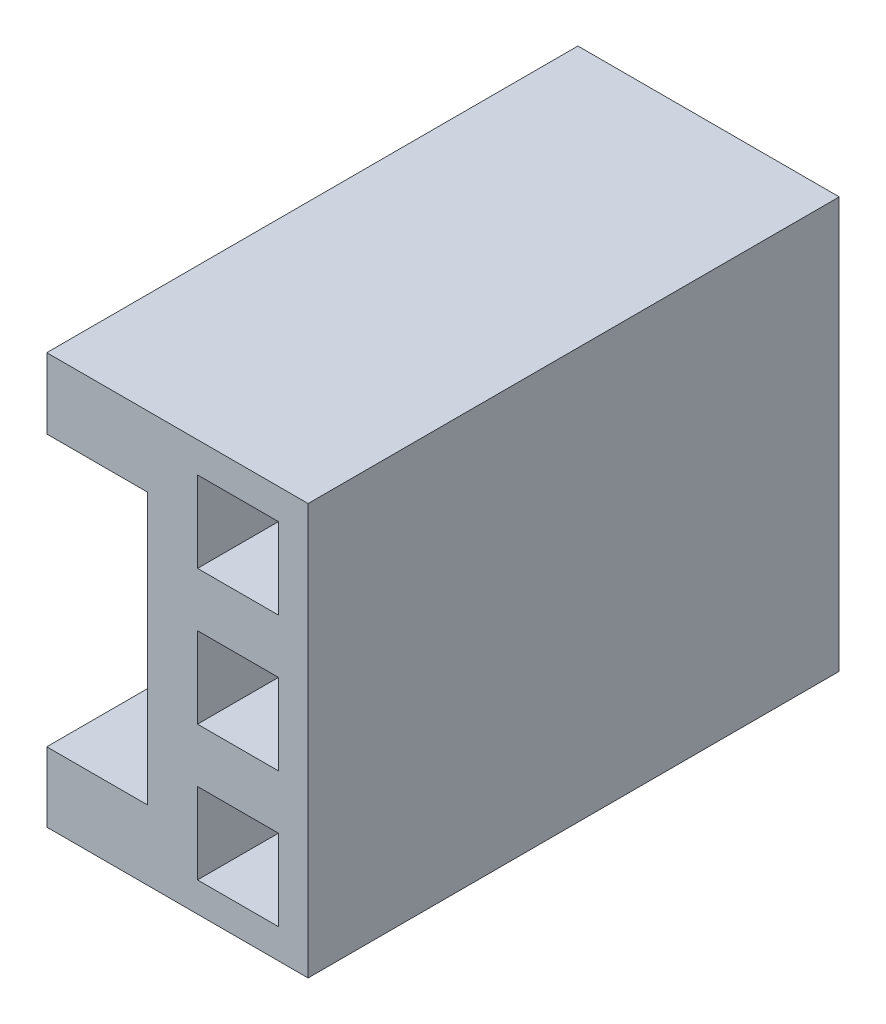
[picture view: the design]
ISO-10303-21;
HEADER;
FILE_DESCRIPTION(('STEP AP214'),'2;1');
FILE_NAME('part.step','',(''),(''),'','','');
FILE_SCHEMA(('AUTOMOTIVE_DESIGN { 1 0 10303 214 1 1 1 1 }'));
ENDSEC;
DATA;
#1=APPLICATION_CONTEXT('core data for automotive mechanical design processes');
#2=APPLICATION_PROTOCOL_DEFINITION('international standard','automotive_design',2000,#1);
#3=PRODUCT_CONTEXT('',#1,'mechanical');
#4=PRODUCT('Part','Part','',(#3));
#5=PRODUCT_RELATED_PRODUCT_CATEGORY('part','',(#4));
#6=PRODUCT_DEFINITION_FORMATION('','',#4);
#7=PRODUCT_DEFINITION_CONTEXT('part definition',#1,'design');
#8=PRODUCT_DEFINITION('design','',#6,#7);
#9=PRODUCT_DEFINITION_SHAPE('','',#8);
#10=(LENGTH_UNIT() NAMED_UNIT(*) SI_UNIT(.MILLI.,.METRE.));
#11=(NAMED_UNIT(*) PLANE_ANGLE_UNIT() SI_UNIT($,.RADIAN.));
#12=(NAMED_UNIT(*) SI_UNIT($,.STERADIAN.) SOLID_ANGLE_UNIT());
#13=UNCERTAINTY_MEASURE_WITH_UNIT(LENGTH_MEASURE(1.E-05),#10,'distance_accuracy_value','');
#14=(GEOMETRIC_REPRESENTATION_CONTEXT(3) GLOBAL_UNCERTAINTY_ASSIGNED_CONTEXT((#13)) GLOBAL_UNIT_ASSIGNED_CONTEXT((#10,
#11,#12)) REPRESENTATION_CONTEXT('',''));
#15=CARTESIAN_POINT('',(0.,0.,0.));
#16=DIRECTION('',(0.,0.,1.));
#17=DIRECTION('',(1.,0.,0.));
#18=AXIS2_PLACEMENT_3D('',#15,#16,#17);
#19=CARTESIAN_POINT('',(-1.69999999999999,-2.54999999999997,10.));
#20=DIRECTION('',(-1.,0.,0.));
#21=DIRECTION('',(0.,0.,1.));
#22=AXIS2_PLACEMENT_3D('',#19,#20,#21);
#23=PLANE('',#22);
#24=DIRECTION('',(0.,0.,-1.));
#25=VECTOR('',#24,1.);
#26=CARTESIAN_POINT('',(-1.69999999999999,-2.54999999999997,10.));
#27=LINE('',#26,#25);
#28=CARTESIAN_POINT('',(-1.69999999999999,-2.54999999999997,1.99999999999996));
#29=VERTEX_POINT('',#28);
#30=CARTESIAN_POINT('',(-1.69999999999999,-2.54999999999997,0.));
#31=VERTEX_POINT('',#30);
#32=EDGE_CURVE('E493',#29,#31,#27,.T.);
#33=ORIENTED_EDGE('',*,*,#32,.F.);
#34=DIRECTION('',(0.,1.,0.));
#35=VECTOR('',#34,1.);
#36=CARTESIAN_POINT('',(-1.69999999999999,-4.56556443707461,1.99999999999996));
#37=LINE('',#36,#35);
#38=CARTESIAN_POINT('',(-1.69999999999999,2.55000000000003,1.99999999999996));
#39=VERTEX_POINT('',#38);
#40=EDGE_CURVE('E291',#29,#39,#37,.T.);
#41=ORIENTED_EDGE('',*,*,#40,.T.);
#42=DIRECTION('',(0.,0.,-1.));
#43=VECTOR('',#42,1.);
#44=CARTESIAN_POINT('',(-1.69999999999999,2.55000000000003,10.));
#45=LINE('',#44,#43);
#46=CARTESIAN_POINT('',(-1.69999999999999,2.55000000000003,0.));
#47=VERTEX_POINT('',#46);
#48=EDGE_CURVE('E490',#39,#47,#45,.T.);
#49=ORIENTED_EDGE('',*,*,#48,.T.);
#50=DIRECTION('',(0.,1.,0.));
#51=VECTOR('',#50,1.);
#52=CARTESIAN_POINT('',(-1.69999999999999,-2.54999999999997,0.));
#53=LINE('',#52,#51);
#54=EDGE_CURVE('E479',#31,#47,#53,.T.);
#55=ORIENTED_EDGE('',*,*,#54,.F.);
#56=EDGE_LOOP('',(#33,#41,#49,#55));
#57=FACE_BOUND('',#56,.T.);
#58=ADVANCED_FACE('F30',(#57),#23,.T.);
#59=CARTESIAN_POINT('',(-1.69999999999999,2.55000000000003,10.));
#60=VERTEX_POINT('',#59);
#61=CARTESIAN_POINT('',(-1.69999999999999,2.55000000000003,3.99999999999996));
#62=VERTEX_POINT('',#61);
#63=EDGE_CURVE('E491',#60,#62,#45,.T.);
#64=ORIENTED_EDGE('',*,*,#63,.T.);
#65=DIRECTION('',(0.,1.,0.));
#66=VECTOR('',#65,1.);
#67=CARTESIAN_POINT('',(-1.69999999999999,-4.56556443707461,3.99999999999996));
#68=LINE('',#67,#66);
#69=CARTESIAN_POINT('',(-1.69999999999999,-2.54999999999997,3.99999999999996));
#70=VERTEX_POINT('',#69);
#71=EDGE_CURVE('E273',#70,#62,#68,.T.);
#72=ORIENTED_EDGE('',*,*,#71,.F.);
#73=CARTESIAN_POINT('',(-1.69999999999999,-2.54999999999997,10.));
#74=VERTEX_POINT('',#73);
#75=EDGE_CURVE('E494',#74,#70,#27,.T.);
#76=ORIENTED_EDGE('',*,*,#75,.F.);
#77=DIRECTION('',(0.,1.,0.));
#78=VECTOR('',#77,1.);
#79=CARTESIAN_POINT('',(-1.69999999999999,-2.54999999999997,10.));
#80=LINE('',#79,#78);
#81=EDGE_CURVE('E486',#74,#60,#80,.T.);
#82=ORIENTED_EDGE('',*,*,#81,.T.);
#83=EDGE_LOOP('',(#64,#72,#76,#82));
#84=FACE_BOUND('',#83,.T.);
#85=ADVANCED_FACE('F570',(#84),#23,.T.);
#86=CARTESIAN_POINT('',(-3.59999999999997,3.87599999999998,10.));
#87=DIRECTION('',(1.,0.,0.));
#88=DIRECTION('',(0.,1.,0.));
#89=AXIS2_PLACEMENT_3D('',#86,#87,#88);
#90=PLANE('',#89);
#91=DIRECTION('',(0.,-1.,0.));
#92=VECTOR('',#91,1.);
#93=CARTESIAN_POINT('',(-3.59999999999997,3.87599999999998,10.));
#94=LINE('',#93,#92);
#95=CARTESIAN_POINT('',(-3.59999999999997,-2.54999999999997,10.));
#96=VERTEX_POINT('',#95);
#97=CARTESIAN_POINT('',(-3.59999999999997,-3.86000000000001,10.));
#98=VERTEX_POINT('',#97);
#99=EDGE_CURVE('E511',#96,#98,#94,.T.);
#100=ORIENTED_EDGE('',*,*,#99,.F.);
#101=DIRECTION('',(0.,0.,-1.));
#102=VECTOR('',#101,1.);
#103=CARTESIAN_POINT('',(-3.59999999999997,-2.54999999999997,10.));
#104=LINE('',#103,#102);
#105=CARTESIAN_POINT('',(-3.59999999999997,-2.54999999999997,0.));
#106=VERTEX_POINT('',#105);
#107=EDGE_CURVE('E298',#96,#106,#104,.T.);
#108=ORIENTED_EDGE('',*,*,#107,.T.);
#109=DIRECTION('',(0.,-1.,0.));
#110=VECTOR('',#109,1.);
#111=CARTESIAN_POINT('',(-3.59999999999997,3.87599999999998,0.));
#112=LINE('',#111,#110);
#113=CARTESIAN_POINT('',(-3.59999999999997,-3.86000000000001,0.));
#114=VERTEX_POINT('',#113);
#115=EDGE_CURVE('E500',#106,#114,#112,.T.);
#116=ORIENTED_EDGE('',*,*,#115,.T.);
#117=DIRECTION('',(0.,0.,-1.));
#118=VECTOR('',#117,1.);
#119=CARTESIAN_POINT('',(-3.59999999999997,-3.86000000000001,10.));
#120=LINE('',#119,#118);
#121=EDGE_CURVE('E525',#98,#114,#120,.T.);
#122=ORIENTED_EDGE('',*,*,#121,.F.);
#123=EDGE_LOOP('',(#100,#108,#116,#122));
#124=FACE_BOUND('',#123,.T.);
#125=ADVANCED_FACE('F576',(#124),#90,.F.);
#126=CARTESIAN_POINT('',(1.32000000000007,3.87599999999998,10.));
#127=DIRECTION('',(0.,0.,-1.));
#128=DIRECTION('',(-1.,0.,0.));
#129=AXIS2_PLACEMENT_3D('',#126,#127,#128);
#130=PLANE('',#129);
#131=DIRECTION('',(1.,0.,0.));
#132=VECTOR('',#131,1.);
#133=CARTESIAN_POINT('',(-0.762000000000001,1.77799999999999,10.));
#134=LINE('',#133,#132);
#135=CARTESIAN_POINT('',(-0.762000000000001,1.77799999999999,10.));
#136=VERTEX_POINT('',#135);
#137=CARTESIAN_POINT('',(0.761999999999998,1.77799999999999,10.));
#138=VERTEX_POINT('',#137);
#139=EDGE_CURVE('E305',#136,#138,#134,.T.);
#140=ORIENTED_EDGE('',*,*,#139,.F.);
#141=DIRECTION('',(0.,-1.,0.));
#142=VECTOR('',#141,1.);
#143=CARTESIAN_POINT('',(-0.762000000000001,1.77799999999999,10.));
#144=LINE('',#143,#142);
#145=CARTESIAN_POINT('',(-0.762000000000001,3.30199999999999,10.));
#146=VERTEX_POINT('',#145);
#147=EDGE_CURVE('E53',#146,#136,#144,.T.);
#148=ORIENTED_EDGE('',*,*,#147,.F.);
#149=DIRECTION('',(-1.,0.,0.));
#150=VECTOR('',#149,1.);
#151=CARTESIAN_POINT('',(-0.762000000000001,3.30199999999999,10.));
#152=LINE('',#151,#150);
#153=CARTESIAN_POINT('',(0.761999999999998,3.30199999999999,10.));
#154=VERTEX_POINT('',#153);
#155=EDGE_CURVE('E311',#154,#146,#152,.T.);
#156=ORIENTED_EDGE('',*,*,#155,.F.);
#157=DIRECTION('',(0.,1.,0.));
#158=VECTOR('',#157,1.);
#159=CARTESIAN_POINT('',(0.761999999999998,1.77799999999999,10.));
#160=LINE('',#159,#158);
#161=EDGE_CURVE('E308',#138,#154,#160,.T.);
#162=ORIENTED_EDGE('',*,*,#161,.F.);
#163=EDGE_LOOP('',(#140,#148,#156,#162));
#164=FACE_BOUND('',#163,.T.);
#165=DIRECTION('',(1.,0.,0.));
#166=VECTOR('',#165,1.);
#167=CARTESIAN_POINT('',(-0.762000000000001,-0.762000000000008,10.));
#168=LINE('',#167,#166);
#169=CARTESIAN_POINT('',(-0.762000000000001,-0.762000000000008,10.));
#170=VERTEX_POINT('',#169);
#171=CARTESIAN_POINT('',(0.761999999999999,-0.762000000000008,10.));
#172=VERTEX_POINT('',#171);
#173=EDGE_CURVE('E342',#170,#172,#168,.T.);
#174=ORIENTED_EDGE('',*,*,#173,.F.);
#175=DIRECTION('',(0.,-1.,0.));
#176=VECTOR('',#175,1.);
#177=CARTESIAN_POINT('',(-0.762000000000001,-0.762000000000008,10.));
#178=LINE('',#177,#176);
#179=CARTESIAN_POINT('',(-0.762000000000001,0.761999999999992,10.));
#180=VERTEX_POINT('',#179);
#181=EDGE_CURVE('E340',#180,#170,#178,.T.);
#182=ORIENTED_EDGE('',*,*,#181,.F.);
#183=DIRECTION('',(-1.,0.,0.));
#184=VECTOR('',#183,1.);
#185=CARTESIAN_POINT('',(-0.762000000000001,0.761999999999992,10.));
#186=LINE('',#185,#184);
#187=CARTESIAN_POINT('',(0.761999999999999,0.761999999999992,10.));
#188=VERTEX_POINT('',#187);
#189=EDGE_CURVE('E348',#188,#180,#186,.T.);
#190=ORIENTED_EDGE('',*,*,#189,.F.);
#191=DIRECTION('',(0.,1.,0.));
#192=VECTOR('',#191,1.);
#193=CARTESIAN_POINT('',(0.761999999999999,-0.762000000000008,10.));
#194=LINE('',#193,#192);
#195=EDGE_CURVE('E345',#172,#188,#194,.T.);
#196=ORIENTED_EDGE('',*,*,#195,.F.);
#197=EDGE_LOOP('',(#174,#182,#190,#196));
#198=FACE_BOUND('',#197,.T.);
#199=DIRECTION('',(1.,0.,0.));
#200=VECTOR('',#199,1.);
#201=CARTESIAN_POINT('',(-0.762,-3.30200000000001,10.));
#202=LINE('',#201,#200);
#203=CARTESIAN_POINT('',(-0.762,-3.30200000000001,10.));
#204=VERTEX_POINT('',#203);
#205=CARTESIAN_POINT('',(0.762,-3.30200000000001,10.));
#206=VERTEX_POINT('',#205);
#207=EDGE_CURVE('E380',#204,#206,#202,.T.);
#208=ORIENTED_EDGE('',*,*,#207,.F.);
#209=DIRECTION('',(0.,-1.,0.));
#210=VECTOR('',#209,1.);
#211=CARTESIAN_POINT('',(-0.762,-3.30200000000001,10.));
#212=LINE('',#211,#210);
#213=CARTESIAN_POINT('',(-0.762,-1.77800000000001,10.));
#214=VERTEX_POINT('',#213);
#215=EDGE_CURVE('E378',#214,#204,#212,.T.);
#216=ORIENTED_EDGE('',*,*,#215,.F.);
#217=DIRECTION('',(-1.,0.,0.));
#218=VECTOR('',#217,1.);
#219=CARTESIAN_POINT('',(-0.762,-1.77800000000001,10.));
#220=LINE('',#219,#218);
#221=CARTESIAN_POINT('',(0.762,-1.77800000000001,10.));
#222=VERTEX_POINT('',#221);
#223=EDGE_CURVE('E386',#222,#214,#220,.T.);
#224=ORIENTED_EDGE('',*,*,#223,.F.);
#225=DIRECTION('',(0.,1.,0.));
#226=VECTOR('',#225,1.);
#227=CARTESIAN_POINT('',(0.762,-3.30200000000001,10.));
#228=LINE('',#227,#226);
#229=EDGE_CURVE('E383',#206,#222,#228,.T.);
#230=ORIENTED_EDGE('',*,*,#229,.F.);
#231=EDGE_LOOP('',(#208,#216,#224,#230));
#232=FACE_BOUND('',#231,.T.);
#233=DIRECTION('',(1.,0.,0.));
#234=VECTOR('',#233,1.);
#235=CARTESIAN_POINT('',(-2.59999999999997,-2.54999999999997,10.));
#236=LINE('',#235,#234);
#237=EDGE_CURVE('E484',#96,#74,#236,.T.);
#238=ORIENTED_EDGE('',*,*,#237,.F.);
#239=ORIENTED_EDGE('',*,*,#99,.T.);
#240=DIRECTION('',(1.,0.,0.));
#241=VECTOR('',#240,1.);
#242=CARTESIAN_POINT('',(-3.59999999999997,-3.86000000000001,10.));
#243=LINE('',#242,#241);
#244=CARTESIAN_POINT('',(1.32000000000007,-3.86000000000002,10.));
#245=VERTEX_POINT('',#244);
#246=EDGE_CURVE('E515',#98,#245,#243,.T.);
#247=ORIENTED_EDGE('',*,*,#246,.T.);
#248=DIRECTION('',(0.,1.,0.));
#249=VECTOR('',#248,1.);
#250=CARTESIAN_POINT('',(1.32000000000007,-3.86000000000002,10.));
#251=LINE('',#250,#249);
#252=CARTESIAN_POINT('',(1.32000000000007,3.87599999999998,10.));
#253=VERTEX_POINT('',#252);
#254=EDGE_CURVE('E517',#245,#253,#251,.T.);
#255=ORIENTED_EDGE('',*,*,#254,.T.);
#256=DIRECTION('',(-1.,0.,0.));
#257=VECTOR('',#256,1.);
#258=CARTESIAN_POINT('',(1.32000000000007,3.87599999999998,10.));
#259=LINE('',#258,#257);
#260=CARTESIAN_POINT('',(-3.59999999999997,3.87599999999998,10.));
#261=VERTEX_POINT('',#260);
#262=EDGE_CURVE('E508',#253,#261,#259,.T.);
#263=ORIENTED_EDGE('',*,*,#262,.T.);
#264=CARTESIAN_POINT('',(-3.59999999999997,2.55000000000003,10.));
#265=VERTEX_POINT('',#264);
#266=EDGE_CURVE('E512',#261,#265,#94,.T.);
#267=ORIENTED_EDGE('',*,*,#266,.T.);
#268=DIRECTION('',(-1.,0.,0.));
#269=VECTOR('',#268,1.);
#270=CARTESIAN_POINT('',(-1.69999999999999,2.55000000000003,10.));
#271=LINE('',#270,#269);
#272=EDGE_CURVE('E488',#60,#265,#271,.T.);
#273=ORIENTED_EDGE('',*,*,#272,.F.);
#274=ORIENTED_EDGE('',*,*,#81,.F.);
#275=EDGE_LOOP('',(#238,#239,#247,#255,#263,#267,#273,#274));
#276=FACE_BOUND('',#275,.T.);
#277=ADVANCED_FACE('F589',(#164,#198,#232,#276),#130,.F.);
#278=CARTESIAN_POINT('',(1.32000000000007,3.87599999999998,0.));
#279=DIRECTION('',(0.,0.,-1.));
#280=DIRECTION('',(-1.,0.,0.));
#281=AXIS2_PLACEMENT_3D('',#278,#279,#280);
#282=PLANE('',#281);
#283=ORIENTED_EDGE('',*,*,#115,.F.);
#284=DIRECTION('',(1.,0.,0.));
#285=VECTOR('',#284,1.);
#286=CARTESIAN_POINT('',(-2.59999999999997,-2.54999999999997,0.));
#287=LINE('',#286,#285);
#288=EDGE_CURVE('E476',#106,#31,#287,.T.);
#289=ORIENTED_EDGE('',*,*,#288,.T.);
#290=ORIENTED_EDGE('',*,*,#54,.T.);
#291=DIRECTION('',(-1.,0.,0.));
#292=VECTOR('',#291,1.);
#293=CARTESIAN_POINT('',(-1.69999999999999,2.55000000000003,0.));
#294=LINE('',#293,#292);
#295=CARTESIAN_POINT('',(-3.59999999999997,2.55000000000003,0.));
#296=VERTEX_POINT('',#295);
#297=EDGE_CURVE('E482',#47,#296,#294,.T.);
#298=ORIENTED_EDGE('',*,*,#297,.T.);
#299=CARTESIAN_POINT('',(-3.59999999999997,3.87599999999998,0.));
#300=VERTEX_POINT('',#299);
#301=EDGE_CURVE('E501',#300,#296,#112,.T.);
#302=ORIENTED_EDGE('',*,*,#301,.F.);
#303=DIRECTION('',(-1.,0.,0.));
#304=VECTOR('',#303,1.);
#305=CARTESIAN_POINT('',(1.32000000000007,3.87599999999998,0.));
#306=LINE('',#305,#304);
#307=CARTESIAN_POINT('',(1.32000000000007,3.87599999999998,0.));
#308=VERTEX_POINT('',#307);
#309=EDGE_CURVE('E497',#308,#300,#306,.T.);
#310=ORIENTED_EDGE('',*,*,#309,.F.);
#311=DIRECTION('',(0.,1.,0.));
#312=VECTOR('',#311,1.);
#313=CARTESIAN_POINT('',(1.32000000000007,-3.86000000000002,0.));
#314=LINE('',#313,#312);
#315=CARTESIAN_POINT('',(1.32000000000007,-3.86000000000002,0.));
#316=VERTEX_POINT('',#315);
#317=EDGE_CURVE('E506',#316,#308,#314,.T.);
#318=ORIENTED_EDGE('',*,*,#317,.F.);
#319=DIRECTION('',(1.,0.,0.));
#320=VECTOR('',#319,1.);
#321=CARTESIAN_POINT('',(-3.59999999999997,-3.86000000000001,0.));
#322=LINE('',#321,#320);
#323=EDGE_CURVE('E504',#114,#316,#322,.T.);
#324=ORIENTED_EDGE('',*,*,#323,.F.);
#325=EDGE_LOOP('',(#283,#289,#290,#298,#302,#310,#318,#324));
#326=FACE_BOUND('',#325,.T.);
#327=DIRECTION('',(0.,-1.,0.));
#328=VECTOR('',#327,1.);
#329=CARTESIAN_POINT('',(-0.32,0.319999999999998,0.));
#330=LINE('',#329,#328);
#331=CARTESIAN_POINT('',(-0.32,0.319999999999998,0.));
#332=VERTEX_POINT('',#331);
#333=CARTESIAN_POINT('',(-0.32,-0.32,0.));
#334=VERTEX_POINT('',#333);
#335=EDGE_CURVE('E445',#332,#334,#330,.T.);
#336=ORIENTED_EDGE('',*,*,#335,.T.);
#337=DIRECTION('',(1.,0.,0.));
#338=VECTOR('',#337,1.);
#339=CARTESIAN_POINT('',(-0.32,-0.32,0.));
#340=LINE('',#339,#338);
#341=CARTESIAN_POINT('',(0.319999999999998,-0.32,0.));
#342=VERTEX_POINT('',#341);
#343=EDGE_CURVE('E436',#334,#342,#340,.T.);
#344=ORIENTED_EDGE('',*,*,#343,.T.);
#345=DIRECTION('',(0.,1.,0.));
#346=VECTOR('',#345,1.);
#347=CARTESIAN_POINT('',(0.319999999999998,-0.32,0.));
#348=LINE('',#347,#346);
#349=CARTESIAN_POINT('',(0.319999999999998,0.319999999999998,0.));
#350=VERTEX_POINT('',#349);
#351=EDGE_CURVE('E439',#342,#350,#348,.T.);
#352=ORIENTED_EDGE('',*,*,#351,.T.);
#353=DIRECTION('',(-1.,0.,0.));
#354=VECTOR('',#353,1.);
#355=CARTESIAN_POINT('',(0.319999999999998,0.319999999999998,0.));
#356=LINE('',#355,#354);
#357=EDGE_CURVE('E442',#350,#332,#356,.T.);
#358=ORIENTED_EDGE('',*,*,#357,.T.);
#359=EDGE_LOOP('',(#336,#344,#352,#358));
#360=FACE_BOUND('',#359,.T.);
#361=DIRECTION('',(0.,-1.,0.));
#362=VECTOR('',#361,1.);
#363=CARTESIAN_POINT('',(-0.32,2.86,0.));
#364=LINE('',#363,#362);
#365=CARTESIAN_POINT('',(-0.32,2.86,0.));
#366=VERTEX_POINT('',#365);
#367=CARTESIAN_POINT('',(-0.32,2.21999999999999,0.));
#368=VERTEX_POINT('',#367);
#369=EDGE_CURVE('E465',#366,#368,#364,.T.);
#370=ORIENTED_EDGE('',*,*,#369,.T.);
#371=DIRECTION('',(1.,0.,0.));
#372=VECTOR('',#371,1.);
#373=CARTESIAN_POINT('',(-0.32,2.21999999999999,0.));
#374=LINE('',#373,#372);
#375=CARTESIAN_POINT('',(0.319999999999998,2.21999999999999,0.));
#376=VERTEX_POINT('',#375);
#377=EDGE_CURVE('E456',#368,#376,#374,.T.);
#378=ORIENTED_EDGE('',*,*,#377,.T.);
#379=DIRECTION('',(0.,1.,0.));
#380=VECTOR('',#379,1.);
#381=CARTESIAN_POINT('',(0.319999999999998,2.21999999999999,0.));
#382=LINE('',#381,#380);
#383=CARTESIAN_POINT('',(0.319999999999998,2.86,0.));
#384=VERTEX_POINT('',#383);
#385=EDGE_CURVE('E459',#376,#384,#382,.T.);
#386=ORIENTED_EDGE('',*,*,#385,.T.);
#387=DIRECTION('',(-1.,0.,0.));
#388=VECTOR('',#387,1.);
#389=CARTESIAN_POINT('',(0.319999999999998,2.86,0.));
#390=LINE('',#389,#388);
#391=EDGE_CURVE('E462',#384,#366,#390,.T.);
#392=ORIENTED_EDGE('',*,*,#391,.T.);
#393=EDGE_LOOP('',(#370,#378,#386,#392));
#394=FACE_BOUND('',#393,.T.);
#395=DIRECTION('',(0.,1.,0.));
#396=VECTOR('',#395,1.);
#397=CARTESIAN_POINT('',(0.319999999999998,-2.86000000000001,0.));
#398=LINE('',#397,#396);
#399=CARTESIAN_POINT('',(0.319999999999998,-2.86000000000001,0.));
#400=VERTEX_POINT('',#399);
#401=CARTESIAN_POINT('',(0.319999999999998,-2.22000000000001,0.));
#402=VERTEX_POINT('',#401);
#403=EDGE_CURVE('E425',#400,#402,#398,.T.);
#404=ORIENTED_EDGE('',*,*,#403,.T.);
#405=DIRECTION('',(-1.,0.,0.));
#406=VECTOR('',#405,1.);
#407=CARTESIAN_POINT('',(0.319999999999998,-2.22000000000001,0.));
#408=LINE('',#407,#406);
#409=CARTESIAN_POINT('',(-0.32,-2.22000000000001,0.));
#410=VERTEX_POINT('',#409);
#411=EDGE_CURVE('E416',#402,#410,#408,.T.);
#412=ORIENTED_EDGE('',*,*,#411,.T.);
#413=DIRECTION('',(0.,-1.,0.));
#414=VECTOR('',#413,1.);
#415=CARTESIAN_POINT('',(-0.32,-2.22000000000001,0.));
#416=LINE('',#415,#414);
#417=CARTESIAN_POINT('',(-0.32,-2.86000000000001,0.));
#418=VERTEX_POINT('',#417);
#419=EDGE_CURVE('E419',#410,#418,#416,.T.);
#420=ORIENTED_EDGE('',*,*,#419,.T.);
#421=DIRECTION('',(1.,0.,0.));
#422=VECTOR('',#421,1.);
#423=CARTESIAN_POINT('',(-0.32,-2.86000000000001,0.));
#424=LINE('',#423,#422);
#425=EDGE_CURVE('E422',#418,#400,#424,.T.);
#426=ORIENTED_EDGE('',*,*,#425,.T.);
#427=EDGE_LOOP('',(#404,#412,#420,#426));
#428=FACE_BOUND('',#427,.T.);
#429=ADVANCED_FACE('F550',(#326,#360,#394,#428),#282,.T.);
#430=CARTESIAN_POINT('',(1.32000000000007,3.87599999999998,10.));
#431=DIRECTION('',(0.,-1.,0.));
#432=DIRECTION('',(0.,0.,-1.));
#433=AXIS2_PLACEMENT_3D('',#430,#431,#432);
#434=PLANE('',#433);
#435=ORIENTED_EDGE('',*,*,#309,.T.);
#436=DIRECTION('',(0.,0.,-1.));
#437=VECTOR('',#436,1.);
#438=CARTESIAN_POINT('',(-3.59999999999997,3.87599999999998,10.));
#439=LINE('',#438,#437);
#440=EDGE_CURVE('E528',#261,#300,#439,.T.);
#441=ORIENTED_EDGE('',*,*,#440,.F.);
#442=ORIENTED_EDGE('',*,*,#262,.F.);
#443=DIRECTION('',(0.,0.,-1.));
#444=VECTOR('',#443,1.);
#445=CARTESIAN_POINT('',(1.32000000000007,3.87599999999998,10.));
#446=LINE('',#445,#444);
#447=EDGE_CURVE('E519',#253,#308,#446,.T.);
#448=ORIENTED_EDGE('',*,*,#447,.T.);
#449=EDGE_LOOP('',(#435,#441,#442,#448));
#450=FACE_BOUND('',#449,.T.);
#451=ADVANCED_FACE('F32',(#450),#434,.F.);
#452=ORIENTED_EDGE('',*,*,#301,.T.);
#453=DIRECTION('',(0.,0.,1.));
#454=VECTOR('',#453,1.);
#455=CARTESIAN_POINT('',(-3.59999999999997,2.55000000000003,0.));
#456=LINE('',#455,#454);
#457=EDGE_CURVE('E301',#296,#265,#456,.T.);
#458=ORIENTED_EDGE('',*,*,#457,.T.);
#459=ORIENTED_EDGE('',*,*,#266,.F.);
#460=ORIENTED_EDGE('',*,*,#440,.T.);
#461=EDGE_LOOP('',(#452,#458,#459,#460));
#462=FACE_BOUND('',#461,.T.);
#463=ADVANCED_FACE('F599',(#462),#90,.F.);
#464=CARTESIAN_POINT('',(-3.59999999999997,-3.86000000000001,10.));
#465=DIRECTION('',(0.,1.,0.));
#466=DIRECTION('',(-1.,0.,0.));
#467=AXIS2_PLACEMENT_3D('',#464,#465,#466);
#468=PLANE('',#467);
#469=ORIENTED_EDGE('',*,*,#323,.T.);
#470=DIRECTION('',(0.,0.,-1.));
#471=VECTOR('',#470,1.);
#472=CARTESIAN_POINT('',(1.32000000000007,-3.86000000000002,10.));
#473=LINE('',#472,#471);
#474=EDGE_CURVE('E522',#245,#316,#473,.T.);
#475=ORIENTED_EDGE('',*,*,#474,.F.);
#476=ORIENTED_EDGE('',*,*,#246,.F.);
#477=ORIENTED_EDGE('',*,*,#121,.T.);
#478=EDGE_LOOP('',(#469,#475,#476,#477));
#479=FACE_BOUND('',#478,.T.);
#480=ADVANCED_FACE('F596',(#479),#468,.F.);
#481=CARTESIAN_POINT('',(1.32000000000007,-3.86000000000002,10.));
#482=DIRECTION('',(-1.,0.,0.));
#483=DIRECTION('',(0.,0.,1.));
#484=AXIS2_PLACEMENT_3D('',#481,#482,#483);
#485=PLANE('',#484);
#486=ORIENTED_EDGE('',*,*,#317,.T.);
#487=ORIENTED_EDGE('',*,*,#447,.F.);
#488=ORIENTED_EDGE('',*,*,#254,.F.);
#489=ORIENTED_EDGE('',*,*,#474,.T.);
#490=EDGE_LOOP('',(#486,#487,#488,#489));
#491=FACE_BOUND('',#490,.T.);
#492=ADVANCED_FACE('F585',(#491),#485,.F.);
#493=CARTESIAN_POINT('',(-2.59999999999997,-2.54999999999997,10.));
#494=DIRECTION('',(0.,1.,0.));
#495=DIRECTION('',(0.,0.,1.));
#496=AXIS2_PLACEMENT_3D('',#493,#494,#495);
#497=PLANE('',#496);
#498=ORIENTED_EDGE('',*,*,#288,.F.);
#499=ORIENTED_EDGE('',*,*,#107,.F.);
#500=ORIENTED_EDGE('',*,*,#237,.T.);
#501=ORIENTED_EDGE('',*,*,#75,.T.);
#502=DIRECTION('',(0.447213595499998,0.,-0.894427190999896));
#503=VECTOR('',#502,1.);
#504=CARTESIAN_POINT('',(-1.69999999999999,-2.54999999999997,3.99999999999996));
#505=LINE('',#504,#503);
#506=CARTESIAN_POINT('',(-1.44999999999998,-2.54999999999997,3.49999999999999));
#507=VERTEX_POINT('',#506);
#508=EDGE_CURVE('E297',#70,#507,#505,.T.);
#509=ORIENTED_EDGE('',*,*,#508,.T.);
#510=DIRECTION('',(0.,0.,-1.));
#511=VECTOR('',#510,1.);
#512=CARTESIAN_POINT('',(-1.44999999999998,-2.54999999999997,3.49999999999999));
#513=LINE('',#512,#511);
#514=CARTESIAN_POINT('',(-1.44999999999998,-2.54999999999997,2.49999999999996));
#515=VERTEX_POINT('',#514);
#516=EDGE_CURVE('E269',#507,#515,#513,.T.);
#517=ORIENTED_EDGE('',*,*,#516,.T.);
#518=DIRECTION('',(-0.447213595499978,0.,-0.894427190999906));
#519=VECTOR('',#518,1.);
#520=CARTESIAN_POINT('',(-1.44999999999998,-2.54999999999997,2.49999999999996));
#521=LINE('',#520,#519);
#522=EDGE_CURVE('E272',#515,#29,#521,.T.);
#523=ORIENTED_EDGE('',*,*,#522,.T.);
#524=ORIENTED_EDGE('',*,*,#32,.T.);
#525=EDGE_LOOP('',(#498,#499,#500,#501,#509,#517,#523,#524));
#526=FACE_BOUND('',#525,.T.);
#527=ADVANCED_FACE('F582',(#526),#497,.T.);
#528=CARTESIAN_POINT('',(-1.69999999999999,2.55000000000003,10.));
#529=DIRECTION('',(0.,-1.,0.));
#530=DIRECTION('',(0.,0.,-1.));
#531=AXIS2_PLACEMENT_3D('',#528,#529,#530);
#532=PLANE('',#531);
#533=ORIENTED_EDGE('',*,*,#297,.F.);
#534=ORIENTED_EDGE('',*,*,#48,.F.);
#535=DIRECTION('',(0.447213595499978,0.,0.894427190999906));
#536=VECTOR('',#535,1.);
#537=CARTESIAN_POINT('',(-1.44999999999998,2.55000000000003,2.49999999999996));
#538=LINE('',#537,#536);
#539=CARTESIAN_POINT('',(-1.44999999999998,2.55000000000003,2.49999999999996));
#540=VERTEX_POINT('',#539);
#541=EDGE_CURVE('E278',#39,#540,#538,.T.);
#542=ORIENTED_EDGE('',*,*,#541,.T.);
#543=DIRECTION('',(0.,0.,1.));
#544=VECTOR('',#543,1.);
#545=CARTESIAN_POINT('',(-1.44999999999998,2.55000000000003,3.49999999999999));
#546=LINE('',#545,#544);
#547=CARTESIAN_POINT('',(-1.44999999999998,2.55000000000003,3.49999999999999));
#548=VERTEX_POINT('',#547);
#549=EDGE_CURVE('E267',#540,#548,#546,.T.);
#550=ORIENTED_EDGE('',*,*,#549,.T.);
#551=DIRECTION('',(-0.447213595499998,0.,0.894427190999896));
#552=VECTOR('',#551,1.);
#553=CARTESIAN_POINT('',(-1.69999999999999,2.55000000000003,3.99999999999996));
#554=LINE('',#553,#552);
#555=EDGE_CURVE('E45',#548,#62,#554,.T.);
#556=ORIENTED_EDGE('',*,*,#555,.T.);
#557=ORIENTED_EDGE('',*,*,#63,.F.);
#558=ORIENTED_EDGE('',*,*,#272,.T.);
#559=ORIENTED_EDGE('',*,*,#457,.F.);
#560=EDGE_LOOP('',(#533,#534,#542,#550,#556,#557,#558,#559));
#561=FACE_BOUND('',#560,.T.);
#562=ADVANCED_FACE('F282',(#561),#532,.T.);
#563=CARTESIAN_POINT('',(-0.32,2.21999999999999,10.));
#564=DIRECTION('',(0.,1.,0.));
#565=DIRECTION('',(0.,0.,1.));
#566=AXIS2_PLACEMENT_3D('',#563,#564,#565);
#567=PLANE('',#566);
#568=DIRECTION('',(-1.,0.,0.));
#569=VECTOR('',#568,1.);
#570=CARTESIAN_POINT('',(-0.32,2.21999999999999,7.46));
#571=LINE('',#570,#569);
#572=CARTESIAN_POINT('',(0.319999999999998,2.21999999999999,7.46));
#573=VERTEX_POINT('',#572);
#574=CARTESIAN_POINT('',(-0.32,2.21999999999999,7.46));
#575=VERTEX_POINT('',#574);
#576=EDGE_CURVE('E338',#573,#575,#571,.T.);
#577=ORIENTED_EDGE('',*,*,#576,.F.);
#578=DIRECTION('',(0.,0.,-1.));
#579=VECTOR('',#578,1.);
#580=CARTESIAN_POINT('',(0.319999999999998,2.21999999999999,10.));
#581=LINE('',#580,#579);
#582=EDGE_CURVE('E474',#573,#376,#581,.T.);
#583=ORIENTED_EDGE('',*,*,#582,.T.);
#584=ORIENTED_EDGE('',*,*,#377,.F.);
#585=DIRECTION('',(0.,0.,-1.));
#586=VECTOR('',#585,1.);
#587=CARTESIAN_POINT('',(-0.32,2.21999999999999,10.));
#588=LINE('',#587,#586);
#589=EDGE_CURVE('E468',#575,#368,#588,.T.);
#590=ORIENTED_EDGE('',*,*,#589,.F.);
#591=EDGE_LOOP('',(#577,#583,#584,#590));
#592=FACE_BOUND('',#591,.T.);
#593=ADVANCED_FACE('F851',(#592),#567,.T.);
#594=CARTESIAN_POINT('',(0.319999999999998,2.21999999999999,10.));
#595=DIRECTION('',(-1.,0.,0.));
#596=DIRECTION('',(0.,0.,1.));
#597=AXIS2_PLACEMENT_3D('',#594,#595,#596);
#598=PLANE('',#597);
#599=DIRECTION('',(0.,-1.,0.));
#600=VECTOR('',#599,1.);
#601=CARTESIAN_POINT('',(0.319999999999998,2.21999999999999,7.46));
#602=LINE('',#601,#600);
#603=CARTESIAN_POINT('',(0.319999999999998,2.86,7.46));
#604=VERTEX_POINT('',#603);
#605=EDGE_CURVE('E336',#604,#573,#602,.T.);
#606=ORIENTED_EDGE('',*,*,#605,.F.);
#607=DIRECTION('',(0.,0.,-1.));
#608=VECTOR('',#607,1.);
#609=CARTESIAN_POINT('',(0.319999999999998,2.86,10.));
#610=LINE('',#609,#608);
#611=EDGE_CURVE('E472',#604,#384,#610,.T.);
#612=ORIENTED_EDGE('',*,*,#611,.T.);
#613=ORIENTED_EDGE('',*,*,#385,.F.);
#614=ORIENTED_EDGE('',*,*,#582,.F.);
#615=EDGE_LOOP('',(#606,#612,#613,#614));
#616=FACE_BOUND('',#615,.T.);
#617=ADVANCED_FACE('F874',(#616),#598,.T.);
#618=CARTESIAN_POINT('',(0.319999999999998,2.86,10.));
#619=DIRECTION('',(0.,-1.,0.));
#620=DIRECTION('',(1.,0.,0.));
#621=AXIS2_PLACEMENT_3D('',#618,#619,#620);
#622=PLANE('',#621);
#623=DIRECTION('',(1.,0.,0.));
#624=VECTOR('',#623,1.);
#625=CARTESIAN_POINT('',(0.319999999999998,2.86,7.46));
#626=LINE('',#625,#624);
#627=CARTESIAN_POINT('',(-0.32,2.86,7.46));
#628=VERTEX_POINT('',#627);
#629=EDGE_CURVE('E329',#628,#604,#626,.T.);
#630=ORIENTED_EDGE('',*,*,#629,.F.);
#631=DIRECTION('',(0.,0.,-1.));
#632=VECTOR('',#631,1.);
#633=CARTESIAN_POINT('',(-0.32,2.86,10.));
#634=LINE('',#633,#632);
#635=EDGE_CURVE('E470',#628,#366,#634,.T.);
#636=ORIENTED_EDGE('',*,*,#635,.T.);
#637=ORIENTED_EDGE('',*,*,#391,.F.);
#638=ORIENTED_EDGE('',*,*,#611,.F.);
#639=EDGE_LOOP('',(#630,#636,#637,#638));
#640=FACE_BOUND('',#639,.T.);
#641=ADVANCED_FACE('F566',(#640),#622,.T.);
#642=CARTESIAN_POINT('',(-0.32,2.86,10.));
#643=DIRECTION('',(1.,0.,0.));
#644=DIRECTION('',(0.,0.,-1.));
#645=AXIS2_PLACEMENT_3D('',#642,#643,#644);
#646=PLANE('',#645);
#647=DIRECTION('',(0.,1.,0.));
#648=VECTOR('',#647,1.);
#649=CARTESIAN_POINT('',(-0.32,2.86,7.46));
#650=LINE('',#649,#648);
#651=EDGE_CURVE('E11',#575,#628,#650,.T.);
#652=ORIENTED_EDGE('',*,*,#651,.F.);
#653=ORIENTED_EDGE('',*,*,#589,.T.);
#654=ORIENTED_EDGE('',*,*,#369,.F.);
#655=ORIENTED_EDGE('',*,*,#635,.F.);
#656=EDGE_LOOP('',(#652,#653,#654,#655));
#657=FACE_BOUND('',#656,.T.);
#658=ADVANCED_FACE('F559',(#657),#646,.T.);
#659=CARTESIAN_POINT('',(-0.32,-0.32,10.));
#660=DIRECTION('',(0.,1.,0.));
#661=DIRECTION('',(0.,0.,1.));
#662=AXIS2_PLACEMENT_3D('',#659,#660,#661);
#663=PLANE('',#662);
#664=DIRECTION('',(-1.,0.,0.));
#665=VECTOR('',#664,1.);
#666=CARTESIAN_POINT('',(-0.32,-0.32,7.46));
#667=LINE('',#666,#665);
#668=CARTESIAN_POINT('',(0.319999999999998,-0.32,7.46));
#669=VERTEX_POINT('',#668);
#670=CARTESIAN_POINT('',(-0.32,-0.32,7.46));
#671=VERTEX_POINT('',#670);
#672=EDGE_CURVE('E376',#669,#671,#667,.T.);
#673=ORIENTED_EDGE('',*,*,#672,.F.);
#674=DIRECTION('',(0.,0.,-1.));
#675=VECTOR('',#674,1.);
#676=CARTESIAN_POINT('',(0.319999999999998,-0.32,10.));
#677=LINE('',#676,#675);
#678=EDGE_CURVE('E454',#669,#342,#677,.T.);
#679=ORIENTED_EDGE('',*,*,#678,.T.);
#680=ORIENTED_EDGE('',*,*,#343,.F.);
#681=DIRECTION('',(0.,0.,-1.));
#682=VECTOR('',#681,1.);
#683=CARTESIAN_POINT('',(-0.32,-0.32,10.));
#684=LINE('',#683,#682);
#685=EDGE_CURVE('E448',#671,#334,#684,.T.);
#686=ORIENTED_EDGE('',*,*,#685,.F.);
#687=EDGE_LOOP('',(#673,#679,#680,#686));
#688=FACE_BOUND('',#687,.T.);
#689=ADVANCED_FACE('F557',(#688),#663,.T.);
#690=CARTESIAN_POINT('',(0.319999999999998,-0.32,10.));
#691=DIRECTION('',(-1.,0.,0.));
#692=DIRECTION('',(0.,0.,1.));
#693=AXIS2_PLACEMENT_3D('',#690,#691,#692);
#694=PLANE('',#693);
#695=DIRECTION('',(0.,-1.,0.));
#696=VECTOR('',#695,1.);
#697=CARTESIAN_POINT('',(0.319999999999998,-0.32,7.46));
#698=LINE('',#697,#696);
#699=CARTESIAN_POINT('',(0.319999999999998,0.319999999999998,7.46));
#700=VERTEX_POINT('',#699);
#701=EDGE_CURVE('E374',#700,#669,#698,.T.);
#702=ORIENTED_EDGE('',*,*,#701,.F.);
#703=DIRECTION('',(0.,0.,-1.));
#704=VECTOR('',#703,1.);
#705=CARTESIAN_POINT('',(0.319999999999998,0.319999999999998,10.));
#706=LINE('',#705,#704);
#707=EDGE_CURVE('E452',#700,#350,#706,.T.);
#708=ORIENTED_EDGE('',*,*,#707,.T.);
#709=ORIENTED_EDGE('',*,*,#351,.F.);
#710=ORIENTED_EDGE('',*,*,#678,.F.);
#711=EDGE_LOOP('',(#702,#708,#709,#710));
#712=FACE_BOUND('',#711,.T.);
#713=ADVANCED_FACE('F555',(#712),#694,.T.);
#714=CARTESIAN_POINT('',(0.319999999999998,0.319999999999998,10.));
#715=DIRECTION('',(0.,-1.,0.));
#716=DIRECTION('',(0.,0.,-1.));
#717=AXIS2_PLACEMENT_3D('',#714,#715,#716);
#718=PLANE('',#717);
#719=DIRECTION('',(1.,0.,0.));
#720=VECTOR('',#719,1.);
#721=CARTESIAN_POINT('',(0.319999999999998,0.319999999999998,7.46));
#722=LINE('',#721,#720);
#723=CARTESIAN_POINT('',(-0.32,0.319999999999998,7.46));
#724=VERTEX_POINT('',#723);
#725=EDGE_CURVE('E366',#724,#700,#722,.T.);
#726=ORIENTED_EDGE('',*,*,#725,.F.);
#727=DIRECTION('',(0.,0.,-1.));
#728=VECTOR('',#727,1.);
#729=CARTESIAN_POINT('',(-0.32,0.319999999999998,10.));
#730=LINE('',#729,#728);
#731=EDGE_CURVE('E450',#724,#332,#730,.T.);
#732=ORIENTED_EDGE('',*,*,#731,.T.);
#733=ORIENTED_EDGE('',*,*,#357,.F.);
#734=ORIENTED_EDGE('',*,*,#707,.F.);
#735=EDGE_LOOP('',(#726,#732,#733,#734));
#736=FACE_BOUND('',#735,.T.);
#737=ADVANCED_FACE('F544',(#736),#718,.T.);
#738=CARTESIAN_POINT('',(-0.32,0.319999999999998,10.));
#739=DIRECTION('',(1.,0.,0.));
#740=DIRECTION('',(0.,0.,-1.));
#741=AXIS2_PLACEMENT_3D('',#738,#739,#740);
#742=PLANE('',#741);
#743=DIRECTION('',(0.,1.,0.));
#744=VECTOR('',#743,1.);
#745=CARTESIAN_POINT('',(-0.32,0.319999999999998,7.46));
#746=LINE('',#745,#744);
#747=EDGE_CURVE('E38',#671,#724,#746,.T.);
#748=ORIENTED_EDGE('',*,*,#747,.F.);
#749=ORIENTED_EDGE('',*,*,#685,.T.);
#750=ORIENTED_EDGE('',*,*,#335,.F.);
#751=ORIENTED_EDGE('',*,*,#731,.F.);
#752=EDGE_LOOP('',(#748,#749,#750,#751));
#753=FACE_BOUND('',#752,.T.);
#754=ADVANCED_FACE('F547',(#753),#742,.T.);
#755=CARTESIAN_POINT('',(0.319999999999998,-2.22000000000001,10.));
#756=DIRECTION('',(0.,-1.,0.));
#757=DIRECTION('',(1.,0.,0.));
#758=AXIS2_PLACEMENT_3D('',#755,#756,#757);
#759=PLANE('',#758);
#760=DIRECTION('',(1.,0.,0.));
#761=VECTOR('',#760,1.);
#762=CARTESIAN_POINT('',(0.319999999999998,-2.22000000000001,7.46));
#763=LINE('',#762,#761);
#764=CARTESIAN_POINT('',(-0.32,-2.22000000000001,7.46));
#765=VERTEX_POINT('',#764);
#766=CARTESIAN_POINT('',(0.319999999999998,-2.22000000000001,7.46));
#767=VERTEX_POINT('',#766);
#768=EDGE_CURVE('E414',#765,#767,#763,.T.);
#769=ORIENTED_EDGE('',*,*,#768,.F.);
#770=DIRECTION('',(0.,0.,-1.));
#771=VECTOR('',#770,1.);
#772=CARTESIAN_POINT('',(-0.32,-2.22000000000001,10.));
#773=LINE('',#772,#771);
#774=EDGE_CURVE('E434',#765,#410,#773,.T.);
#775=ORIENTED_EDGE('',*,*,#774,.T.);
#776=ORIENTED_EDGE('',*,*,#411,.F.);
#777=DIRECTION('',(0.,0.,-1.));
#778=VECTOR('',#777,1.);
#779=CARTESIAN_POINT('',(0.319999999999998,-2.22000000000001,10.));
#780=LINE('',#779,#778);
#781=EDGE_CURVE('E428',#767,#402,#780,.T.);
#782=ORIENTED_EDGE('',*,*,#781,.F.);
#783=EDGE_LOOP('',(#769,#775,#776,#782));
#784=FACE_BOUND('',#783,.T.);
#785=ADVANCED_FACE('F709',(#784),#759,.T.);
#786=CARTESIAN_POINT('',(-0.32,-2.22000000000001,10.));
#787=DIRECTION('',(1.,0.,0.));
#788=DIRECTION('',(0.,0.,-1.));
#789=AXIS2_PLACEMENT_3D('',#786,#787,#788);
#790=PLANE('',#789);
#791=DIRECTION('',(0.,1.,0.));
#792=VECTOR('',#791,1.);
#793=CARTESIAN_POINT('',(-0.32,-2.22000000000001,7.46));
#794=LINE('',#793,#792);
#795=CARTESIAN_POINT('',(-0.32,-2.86000000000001,7.46));
#796=VERTEX_POINT('',#795);
#797=EDGE_CURVE('E412',#796,#765,#794,.T.);
#798=ORIENTED_EDGE('',*,*,#797,.F.);
#799=DIRECTION('',(0.,0.,-1.));
#800=VECTOR('',#799,1.);
#801=CARTESIAN_POINT('',(-0.32,-2.86000000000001,10.));
#802=LINE('',#801,#800);
#803=EDGE_CURVE('E432',#796,#418,#802,.T.);
#804=ORIENTED_EDGE('',*,*,#803,.T.);
#805=ORIENTED_EDGE('',*,*,#419,.F.);
#806=ORIENTED_EDGE('',*,*,#774,.F.);
#807=EDGE_LOOP('',(#798,#804,#805,#806));
#808=FACE_BOUND('',#807,.T.);
#809=ADVANCED_FACE('F705',(#808),#790,.T.);
#810=CARTESIAN_POINT('',(-0.32,-2.86000000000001,10.));
#811=DIRECTION('',(0.,1.,0.));
#812=DIRECTION('',(0.,0.,1.));
#813=AXIS2_PLACEMENT_3D('',#810,#811,#812);
#814=PLANE('',#813);
#815=DIRECTION('',(-1.,0.,0.));
#816=VECTOR('',#815,1.);
#817=CARTESIAN_POINT('',(-0.32,-2.86000000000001,7.46));
#818=LINE('',#817,#816);
#819=CARTESIAN_POINT('',(0.319999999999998,-2.86000000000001,7.46));
#820=VERTEX_POINT('',#819);
#821=EDGE_CURVE('E404',#820,#796,#818,.T.);
#822=ORIENTED_EDGE('',*,*,#821,.F.);
#823=DIRECTION('',(0.,0.,-1.));
#824=VECTOR('',#823,1.);
#825=CARTESIAN_POINT('',(0.319999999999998,-2.86000000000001,10.));
#826=LINE('',#825,#824);
#827=EDGE_CURVE('E430',#820,#400,#826,.T.);
#828=ORIENTED_EDGE('',*,*,#827,.T.);
#829=ORIENTED_EDGE('',*,*,#425,.F.);
#830=ORIENTED_EDGE('',*,*,#803,.F.);
#831=EDGE_LOOP('',(#822,#828,#829,#830));
#832=FACE_BOUND('',#831,.T.);
#833=ADVANCED_FACE('F701',(#832),#814,.T.);
#834=CARTESIAN_POINT('',(0.319999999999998,-2.86000000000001,10.));
#835=DIRECTION('',(-1.,0.,0.));
#836=DIRECTION('',(0.,0.,1.));
#837=AXIS2_PLACEMENT_3D('',#834,#835,#836);
#838=PLANE('',#837);
#839=DIRECTION('',(0.,-1.,0.));
#840=VECTOR('',#839,1.);
#841=CARTESIAN_POINT('',(0.319999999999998,-2.86000000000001,7.46));
#842=LINE('',#841,#840);
#843=EDGE_CURVE('E531',#767,#820,#842,.T.);
#844=ORIENTED_EDGE('',*,*,#843,.F.);
#845=ORIENTED_EDGE('',*,*,#781,.T.);
#846=ORIENTED_EDGE('',*,*,#403,.F.);
#847=ORIENTED_EDGE('',*,*,#827,.F.);
#848=EDGE_LOOP('',(#844,#845,#846,#847));
#849=FACE_BOUND('',#848,.T.);
#850=ADVANCED_FACE('F697',(#849),#838,.T.);
#851=CARTESIAN_POINT('',(-0.762,-3.30200000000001,7.46));
#852=DIRECTION('',(-1.,0.,0.));
#853=DIRECTION('',(0.,0.,1.));
#854=AXIS2_PLACEMENT_3D('',#851,#852,#853);
#855=PLANE('',#854);
#856=ORIENTED_EDGE('',*,*,#215,.T.);
#857=DIRECTION('',(0.,0.,1.));
#858=VECTOR('',#857,1.);
#859=CARTESIAN_POINT('',(-0.762,-3.30200000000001,7.46));
#860=LINE('',#859,#858);
#861=CARTESIAN_POINT('',(-0.762,-3.30200000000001,7.46));
#862=VERTEX_POINT('',#861);
#863=EDGE_CURVE('E401',#862,#204,#860,.T.);
#864=ORIENTED_EDGE('',*,*,#863,.F.);
#865=DIRECTION('',(0.,-1.,0.));
#866=VECTOR('',#865,1.);
#867=CARTESIAN_POINT('',(-0.762,-3.30200000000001,7.46));
#868=LINE('',#867,#866);
#869=CARTESIAN_POINT('',(-0.762,-1.77800000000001,7.46));
#870=VERTEX_POINT('',#869);
#871=EDGE_CURVE('E389',#870,#862,#868,.T.);
#872=ORIENTED_EDGE('',*,*,#871,.F.);
#873=DIRECTION('',(0.,0.,1.));
#874=VECTOR('',#873,1.);
#875=CARTESIAN_POINT('',(-0.762,-1.77800000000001,7.46));
#876=LINE('',#875,#874);
#877=EDGE_CURVE('E402',#870,#214,#876,.T.);
#878=ORIENTED_EDGE('',*,*,#877,.T.);
#879=EDGE_LOOP('',(#856,#864,#872,#878));
#880=FACE_BOUND('',#879,.T.);
#881=ADVANCED_FACE('F687',(#880),#855,.F.);
#882=CARTESIAN_POINT('',(-0.762,-1.77800000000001,7.46));
#883=DIRECTION('',(0.,1.,0.));
#884=DIRECTION('',(0.,0.,1.));
#885=AXIS2_PLACEMENT_3D('',#882,#883,#884);
#886=PLANE('',#885);
#887=ORIENTED_EDGE('',*,*,#223,.T.);
#888=ORIENTED_EDGE('',*,*,#877,.F.);
#889=DIRECTION('',(-1.,0.,0.));
#890=VECTOR('',#889,1.);
#891=CARTESIAN_POINT('',(-0.762,-1.77800000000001,7.46));
#892=LINE('',#891,#890);
#893=CARTESIAN_POINT('',(0.762,-1.77800000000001,7.46));
#894=VERTEX_POINT('',#893);
#895=EDGE_CURVE('E398',#894,#870,#892,.T.);
#896=ORIENTED_EDGE('',*,*,#895,.F.);
#897=DIRECTION('',(0.,0.,1.));
#898=VECTOR('',#897,1.);
#899=CARTESIAN_POINT('',(0.762,-1.77800000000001,7.46));
#900=LINE('',#899,#898);
#901=EDGE_CURVE('E405',#894,#222,#900,.T.);
#902=ORIENTED_EDGE('',*,*,#901,.T.);
#903=EDGE_LOOP('',(#887,#888,#896,#902));
#904=FACE_BOUND('',#903,.T.);
#905=ADVANCED_FACE('F683',(#904),#886,.F.);
#906=CARTESIAN_POINT('',(0.762,-3.30200000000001,7.46));
#907=DIRECTION('',(1.,0.,0.));
#908=DIRECTION('',(0.,0.,-1.));
#909=AXIS2_PLACEMENT_3D('',#906,#907,#908);
#910=PLANE('',#909);
#911=ORIENTED_EDGE('',*,*,#229,.T.);
#912=ORIENTED_EDGE('',*,*,#901,.F.);
#913=DIRECTION('',(0.,1.,0.));
#914=VECTOR('',#913,1.);
#915=CARTESIAN_POINT('',(0.762,-3.30200000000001,7.46));
#916=LINE('',#915,#914);
#917=CARTESIAN_POINT('',(0.762,-3.30200000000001,7.46));
#918=VERTEX_POINT('',#917);
#919=EDGE_CURVE('E395',#918,#894,#916,.T.);
#920=ORIENTED_EDGE('',*,*,#919,.F.);
#921=DIRECTION('',(0.,0.,1.));
#922=VECTOR('',#921,1.);
#923=CARTESIAN_POINT('',(0.762,-3.30200000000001,7.46));
#924=LINE('',#923,#922);
#925=EDGE_CURVE('E407',#918,#206,#924,.T.);
#926=ORIENTED_EDGE('',*,*,#925,.T.);
#927=EDGE_LOOP('',(#911,#912,#920,#926));
#928=FACE_BOUND('',#927,.T.);
#929=ADVANCED_FACE('F686',(#928),#910,.F.);
#930=CARTESIAN_POINT('',(-0.762,-3.30200000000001,7.46));
#931=DIRECTION('',(0.,-1.,0.));
#932=DIRECTION('',(0.,0.,-1.));
#933=AXIS2_PLACEMENT_3D('',#930,#931,#932);
#934=PLANE('',#933);
#935=ORIENTED_EDGE('',*,*,#207,.T.);
#936=ORIENTED_EDGE('',*,*,#925,.F.);
#937=DIRECTION('',(1.,0.,0.));
#938=VECTOR('',#937,1.);
#939=CARTESIAN_POINT('',(-0.762,-3.30200000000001,7.46));
#940=LINE('',#939,#938);
#941=EDGE_CURVE('E392',#862,#918,#940,.T.);
#942=ORIENTED_EDGE('',*,*,#941,.F.);
#943=ORIENTED_EDGE('',*,*,#863,.T.);
#944=EDGE_LOOP('',(#935,#936,#942,#943));
#945=FACE_BOUND('',#944,.T.);
#946=ADVANCED_FACE('F681',(#945),#934,.F.);
#947=CARTESIAN_POINT('',(-0.762,-1.77800000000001,7.46));
#948=DIRECTION('',(0.,0.,-1.));
#949=DIRECTION('',(-1.,0.,0.));
#950=AXIS2_PLACEMENT_3D('',#947,#948,#949);
#951=PLANE('',#950);
#952=ORIENTED_EDGE('',*,*,#768,.T.);
#953=ORIENTED_EDGE('',*,*,#843,.T.);
#954=ORIENTED_EDGE('',*,*,#821,.T.);
#955=ORIENTED_EDGE('',*,*,#797,.T.);
#956=EDGE_LOOP('',(#952,#953,#954,#955));
#957=FACE_BOUND('',#956,.T.);
#958=ORIENTED_EDGE('',*,*,#871,.T.);
#959=ORIENTED_EDGE('',*,*,#941,.T.);
#960=ORIENTED_EDGE('',*,*,#919,.T.);
#961=ORIENTED_EDGE('',*,*,#895,.T.);
#962=EDGE_LOOP('',(#958,#959,#960,#961));
#963=FACE_BOUND('',#962,.T.);
#964=ADVANCED_FACE('F677',(#957,#963),#951,.F.);
#965=CARTESIAN_POINT('',(-0.762000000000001,-0.762000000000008,7.46));
#966=DIRECTION('',(-1.,0.,0.));
#967=DIRECTION('',(0.,0.,1.));
#968=AXIS2_PLACEMENT_3D('',#965,#966,#967);
#969=PLANE('',#968);
#970=ORIENTED_EDGE('',*,*,#181,.T.);
#971=DIRECTION('',(0.,0.,1.));
#972=VECTOR('',#971,1.);
#973=CARTESIAN_POINT('',(-0.762000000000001,-0.762000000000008,7.46));
#974=LINE('',#973,#972);
#975=CARTESIAN_POINT('',(-0.762000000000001,-0.762000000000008,7.46));
#976=VERTEX_POINT('',#975);
#977=EDGE_CURVE('E363',#976,#170,#974,.T.);
#978=ORIENTED_EDGE('',*,*,#977,.F.);
#979=DIRECTION('',(0.,-1.,0.));
#980=VECTOR('',#979,1.);
#981=CARTESIAN_POINT('',(-0.762000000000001,-0.762000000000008,7.46));
#982=LINE('',#981,#980);
#983=CARTESIAN_POINT('',(-0.762000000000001,0.761999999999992,7.46));
#984=VERTEX_POINT('',#983);
#985=EDGE_CURVE('E351',#984,#976,#982,.T.);
#986=ORIENTED_EDGE('',*,*,#985,.F.);
#987=DIRECTION('',(0.,0.,1.));
#988=VECTOR('',#987,1.);
#989=CARTESIAN_POINT('',(-0.762000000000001,0.761999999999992,7.46));
#990=LINE('',#989,#988);
#991=EDGE_CURVE('E364',#984,#180,#990,.T.);
#992=ORIENTED_EDGE('',*,*,#991,.T.);
#993=EDGE_LOOP('',(#970,#978,#986,#992));
#994=FACE_BOUND('',#993,.T.);
#995=ADVANCED_FACE('F667',(#994),#969,.F.);
#996=CARTESIAN_POINT('',(-0.762000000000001,0.761999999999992,7.46));
#997=DIRECTION('',(0.,1.,0.));
#998=DIRECTION('',(0.,0.,1.));
#999=AXIS2_PLACEMENT_3D('',#996,#997,#998);
#1000=PLANE('',#999);
#1001=ORIENTED_EDGE('',*,*,#189,.T.);
#1002=ORIENTED_EDGE('',*,*,#991,.F.);
#1003=DIRECTION('',(-1.,0.,0.));
#1004=VECTOR('',#1003,1.);
#1005=CARTESIAN_POINT('',(-0.762000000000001,0.761999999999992,7.46));
#1006=LINE('',#1005,#1004);
#1007=CARTESIAN_POINT('',(0.761999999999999,0.761999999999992,7.46));
#1008=VERTEX_POINT('',#1007);
#1009=EDGE_CURVE('E360',#1008,#984,#1006,.T.);
#1010=ORIENTED_EDGE('',*,*,#1009,.F.);
#1011=DIRECTION('',(0.,0.,1.));
#1012=VECTOR('',#1011,1.);
#1013=CARTESIAN_POINT('',(0.761999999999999,0.761999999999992,7.46));
#1014=LINE('',#1013,#1012);
#1015=EDGE_CURVE('E367',#1008,#188,#1014,.T.);
#1016=ORIENTED_EDGE('',*,*,#1015,.T.);
#1017=EDGE_LOOP('',(#1001,#1002,#1010,#1016));
#1018=FACE_BOUND('',#1017,.T.);
#1019=ADVANCED_FACE('F663',(#1018),#1000,.F.);
#1020=CARTESIAN_POINT('',(0.761999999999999,-0.762000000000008,7.46));
#1021=DIRECTION('',(1.,0.,0.));
#1022=DIRECTION('',(0.,0.,-1.));
#1023=AXIS2_PLACEMENT_3D('',#1020,#1021,#1022);
#1024=PLANE('',#1023);
#1025=ORIENTED_EDGE('',*,*,#195,.T.);
#1026=ORIENTED_EDGE('',*,*,#1015,.F.);
#1027=DIRECTION('',(0.,1.,0.));
#1028=VECTOR('',#1027,1.);
#1029=CARTESIAN_POINT('',(0.761999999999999,-0.762000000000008,7.46));
#1030=LINE('',#1029,#1028);
#1031=CARTESIAN_POINT('',(0.761999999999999,-0.762000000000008,7.46));
#1032=VERTEX_POINT('',#1031);
#1033=EDGE_CURVE('E357',#1032,#1008,#1030,.T.);
#1034=ORIENTED_EDGE('',*,*,#1033,.F.);
#1035=DIRECTION('',(0.,0.,1.));
#1036=VECTOR('',#1035,1.);
#1037=CARTESIAN_POINT('',(0.761999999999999,-0.762000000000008,7.46));
#1038=LINE('',#1037,#1036);
#1039=EDGE_CURVE('E369',#1032,#172,#1038,.T.);
#1040=ORIENTED_EDGE('',*,*,#1039,.T.);
#1041=EDGE_LOOP('',(#1025,#1026,#1034,#1040));
#1042=FACE_BOUND('',#1041,.T.);
#1043=ADVANCED_FACE('F666',(#1042),#1024,.F.);
#1044=CARTESIAN_POINT('',(-0.762000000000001,-0.762000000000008,7.46));
#1045=DIRECTION('',(0.,-1.,0.));
#1046=DIRECTION('',(0.,0.,-1.));
#1047=AXIS2_PLACEMENT_3D('',#1044,#1045,#1046);
#1048=PLANE('',#1047);
#1049=ORIENTED_EDGE('',*,*,#173,.T.);
#1050=ORIENTED_EDGE('',*,*,#1039,.F.);
#1051=DIRECTION('',(1.,0.,0.));
#1052=VECTOR('',#1051,1.);
#1053=CARTESIAN_POINT('',(-0.762000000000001,-0.762000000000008,7.46));
#1054=LINE('',#1053,#1052);
#1055=EDGE_CURVE('E354',#976,#1032,#1054,.T.);
#1056=ORIENTED_EDGE('',*,*,#1055,.F.);
#1057=ORIENTED_EDGE('',*,*,#977,.T.);
#1058=EDGE_LOOP('',(#1049,#1050,#1056,#1057));
#1059=FACE_BOUND('',#1058,.T.);
#1060=ADVANCED_FACE('F662',(#1059),#1048,.F.);
#1061=CARTESIAN_POINT('',(-0.762000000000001,0.761999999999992,7.46));
#1062=DIRECTION('',(0.,0.,-1.));
#1063=DIRECTION('',(-1.,0.,0.));
#1064=AXIS2_PLACEMENT_3D('',#1061,#1062,#1063);
#1065=PLANE('',#1064);
#1066=ORIENTED_EDGE('',*,*,#672,.T.);
#1067=ORIENTED_EDGE('',*,*,#747,.T.);
#1068=ORIENTED_EDGE('',*,*,#725,.T.);
#1069=ORIENTED_EDGE('',*,*,#701,.T.);
#1070=EDGE_LOOP('',(#1066,#1067,#1068,#1069));
#1071=FACE_BOUND('',#1070,.T.);
#1072=ORIENTED_EDGE('',*,*,#985,.T.);
#1073=ORIENTED_EDGE('',*,*,#1055,.T.);
#1074=ORIENTED_EDGE('',*,*,#1033,.T.);
#1075=ORIENTED_EDGE('',*,*,#1009,.T.);
#1076=EDGE_LOOP('',(#1072,#1073,#1074,#1075));
#1077=FACE_BOUND('',#1076,.T.);
#1078=ADVANCED_FACE('F535',(#1071,#1077),#1065,.F.);
#1079=CARTESIAN_POINT('',(-0.762000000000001,1.77799999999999,7.46));
#1080=DIRECTION('',(-1.,0.,0.));
#1081=DIRECTION('',(0.,0.,1.));
#1082=AXIS2_PLACEMENT_3D('',#1079,#1080,#1081);
#1083=PLANE('',#1082);
#1084=ORIENTED_EDGE('',*,*,#147,.T.);
#1085=DIRECTION('',(0.,0.,1.));
#1086=VECTOR('',#1085,1.);
#1087=CARTESIAN_POINT('',(-0.762000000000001,1.77799999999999,7.46));
#1088=LINE('',#1087,#1086);
#1089=CARTESIAN_POINT('',(-0.762000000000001,1.77799999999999,7.46));
#1090=VERTEX_POINT('',#1089);
#1091=EDGE_CURVE('E326',#1090,#136,#1088,.T.);
#1092=ORIENTED_EDGE('',*,*,#1091,.F.);
#1093=DIRECTION('',(0.,-1.,0.));
#1094=VECTOR('',#1093,1.);
#1095=CARTESIAN_POINT('',(-0.762000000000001,1.77799999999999,7.46));
#1096=LINE('',#1095,#1094);
#1097=CARTESIAN_POINT('',(-0.762000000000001,3.30199999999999,7.46));
#1098=VERTEX_POINT('',#1097);
#1099=EDGE_CURVE('E314',#1098,#1090,#1096,.T.);
#1100=ORIENTED_EDGE('',*,*,#1099,.F.);
#1101=DIRECTION('',(0.,0.,1.));
#1102=VECTOR('',#1101,1.);
#1103=CARTESIAN_POINT('',(-0.762000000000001,3.30199999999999,7.46));
#1104=LINE('',#1103,#1102);
#1105=EDGE_CURVE('E327',#1098,#146,#1104,.T.);
#1106=ORIENTED_EDGE('',*,*,#1105,.T.);
#1107=EDGE_LOOP('',(#1084,#1092,#1100,#1106));
#1108=FACE_BOUND('',#1107,.T.);
#1109=ADVANCED_FACE('F650',(#1108),#1083,.F.);
#1110=CARTESIAN_POINT('',(-0.762000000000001,3.30199999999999,7.46));
#1111=DIRECTION('',(0.,1.,0.));
#1112=DIRECTION('',(0.,0.,1.));
#1113=AXIS2_PLACEMENT_3D('',#1110,#1111,#1112);
#1114=PLANE('',#1113);
#1115=ORIENTED_EDGE('',*,*,#155,.T.);
#1116=ORIENTED_EDGE('',*,*,#1105,.F.);
#1117=DIRECTION('',(-1.,0.,0.));
#1118=VECTOR('',#1117,1.);
#1119=CARTESIAN_POINT('',(-0.762000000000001,3.30199999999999,7.46));
#1120=LINE('',#1119,#1118);
#1121=CARTESIAN_POINT('',(0.761999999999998,3.30199999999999,7.46));
#1122=VERTEX_POINT('',#1121);
#1123=EDGE_CURVE('E323',#1122,#1098,#1120,.T.);
#1124=ORIENTED_EDGE('',*,*,#1123,.F.);
#1125=DIRECTION('',(0.,0.,1.));
#1126=VECTOR('',#1125,1.);
#1127=CARTESIAN_POINT('',(0.761999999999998,3.30199999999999,7.46));
#1128=LINE('',#1127,#1126);
#1129=EDGE_CURVE('E330',#1122,#154,#1128,.T.);
#1130=ORIENTED_EDGE('',*,*,#1129,.T.);
#1131=EDGE_LOOP('',(#1115,#1116,#1124,#1130));
#1132=FACE_BOUND('',#1131,.T.);
#1133=ADVANCED_FACE('F646',(#1132),#1114,.F.);
#1134=CARTESIAN_POINT('',(0.761999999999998,1.77799999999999,7.46));
#1135=DIRECTION('',(1.,0.,0.));
#1136=DIRECTION('',(0.,0.,-1.));
#1137=AXIS2_PLACEMENT_3D('',#1134,#1135,#1136);
#1138=PLANE('',#1137);
#1139=ORIENTED_EDGE('',*,*,#161,.T.);
#1140=ORIENTED_EDGE('',*,*,#1129,.F.);
#1141=DIRECTION('',(0.,1.,0.));
#1142=VECTOR('',#1141,1.);
#1143=CARTESIAN_POINT('',(0.761999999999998,1.77799999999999,7.46));
#1144=LINE('',#1143,#1142);
#1145=CARTESIAN_POINT('',(0.761999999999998,1.77799999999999,7.46));
#1146=VERTEX_POINT('',#1145);
#1147=EDGE_CURVE('E320',#1146,#1122,#1144,.T.);
#1148=ORIENTED_EDGE('',*,*,#1147,.F.);
#1149=DIRECTION('',(0.,0.,1.));
#1150=VECTOR('',#1149,1.);
#1151=CARTESIAN_POINT('',(0.761999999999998,1.77799999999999,7.46));
#1152=LINE('',#1151,#1150);
#1153=EDGE_CURVE('E332',#1146,#138,#1152,.T.);
#1154=ORIENTED_EDGE('',*,*,#1153,.T.);
#1155=EDGE_LOOP('',(#1139,#1140,#1148,#1154));
#1156=FACE_BOUND('',#1155,.T.);
#1157=ADVANCED_FACE('F649',(#1156),#1138,.F.);
#1158=CARTESIAN_POINT('',(-0.762000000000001,1.77799999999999,7.46));
#1159=DIRECTION('',(0.,-1.,0.));
#1160=DIRECTION('',(0.,0.,-1.));
#1161=AXIS2_PLACEMENT_3D('',#1158,#1159,#1160);
#1162=PLANE('',#1161);
#1163=ORIENTED_EDGE('',*,*,#139,.T.);
#1164=ORIENTED_EDGE('',*,*,#1153,.F.);
#1165=DIRECTION('',(1.,0.,0.));
#1166=VECTOR('',#1165,1.);
#1167=CARTESIAN_POINT('',(-0.762000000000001,1.77799999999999,7.46));
#1168=LINE('',#1167,#1166);
#1169=EDGE_CURVE('E317',#1090,#1146,#1168,.T.);
#1170=ORIENTED_EDGE('',*,*,#1169,.F.);
#1171=ORIENTED_EDGE('',*,*,#1091,.T.);
#1172=EDGE_LOOP('',(#1163,#1164,#1170,#1171));
#1173=FACE_BOUND('',#1172,.T.);
#1174=ADVANCED_FACE('F640',(#1173),#1162,.F.);
#1175=CARTESIAN_POINT('',(-0.762000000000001,3.30199999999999,7.46));
#1176=DIRECTION('',(0.,0.,-1.));
#1177=DIRECTION('',(-1.,0.,0.));
#1178=AXIS2_PLACEMENT_3D('',#1175,#1176,#1177);
#1179=PLANE('',#1178);
#1180=ORIENTED_EDGE('',*,*,#576,.T.);
#1181=ORIENTED_EDGE('',*,*,#651,.T.);
#1182=ORIENTED_EDGE('',*,*,#629,.T.);
#1183=ORIENTED_EDGE('',*,*,#605,.T.);
#1184=EDGE_LOOP('',(#1180,#1181,#1182,#1183));
#1185=FACE_BOUND('',#1184,.T.);
#1186=ORIENTED_EDGE('',*,*,#1099,.T.);
#1187=ORIENTED_EDGE('',*,*,#1169,.T.);
#1188=ORIENTED_EDGE('',*,*,#1147,.T.);
#1189=ORIENTED_EDGE('',*,*,#1123,.T.);
#1190=EDGE_LOOP('',(#1186,#1187,#1188,#1189));
#1191=FACE_BOUND('',#1190,.T.);
#1192=ADVANCED_FACE('F633',(#1185,#1191),#1179,.F.);
#1193=CARTESIAN_POINT('',(-1.44999999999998,-4.56556443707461,2.49999999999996));
#1194=DIRECTION('',(-0.894427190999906,0.,0.447213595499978));
#1195=DIRECTION('',(0.447213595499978,0.,0.894427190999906));
#1196=AXIS2_PLACEMENT_3D('',#1193,#1194,#1195);
#1197=PLANE('',#1196);
#1198=DIRECTION('',(0.,1.,0.));
#1199=VECTOR('',#1198,1.);
#1200=CARTESIAN_POINT('',(-1.44999999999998,-4.56556443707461,2.49999999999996));
#1201=LINE('',#1200,#1199);
#1202=EDGE_CURVE('E289',#515,#540,#1201,.T.);
#1203=ORIENTED_EDGE('',*,*,#1202,.T.);
#1204=ORIENTED_EDGE('',*,*,#541,.F.);
#1205=ORIENTED_EDGE('',*,*,#40,.F.);
#1206=ORIENTED_EDGE('',*,*,#522,.F.);
#1207=EDGE_LOOP('',(#1203,#1204,#1205,#1206));
#1208=FACE_BOUND('',#1207,.T.);
#1209=ADVANCED_FACE('F631',(#1208),#1197,.T.);
#1210=CARTESIAN_POINT('',(-1.69999999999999,-4.56556443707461,3.99999999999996));
#1211=DIRECTION('',(-0.894427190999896,0.,-0.447213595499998));
#1212=DIRECTION('',(-0.447213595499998,0.,0.894427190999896));
#1213=AXIS2_PLACEMENT_3D('',#1210,#1211,#1212);
#1214=PLANE('',#1213);
#1215=ORIENTED_EDGE('',*,*,#71,.T.);
#1216=ORIENTED_EDGE('',*,*,#555,.F.);
#1217=DIRECTION('',(0.,1.,0.));
#1218=VECTOR('',#1217,1.);
#1219=CARTESIAN_POINT('',(-1.44999999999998,-4.56556443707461,3.49999999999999));
#1220=LINE('',#1219,#1218);
#1221=EDGE_CURVE('E264',#507,#548,#1220,.T.);
#1222=ORIENTED_EDGE('',*,*,#1221,.F.);
#1223=ORIENTED_EDGE('',*,*,#508,.F.);
#1224=EDGE_LOOP('',(#1215,#1216,#1222,#1223));
#1225=FACE_BOUND('',#1224,.T.);
#1226=ADVANCED_FACE('F275',(#1225),#1214,.T.);
#1227=CARTESIAN_POINT('',(-1.44999999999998,-4.56556443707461,3.49999999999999));
#1228=DIRECTION('',(-1.,0.,0.));
#1229=DIRECTION('',(0.,0.,1.));
#1230=AXIS2_PLACEMENT_3D('',#1227,#1228,#1229);
#1231=PLANE('',#1230);
#1232=ORIENTED_EDGE('',*,*,#1221,.T.);
#1233=ORIENTED_EDGE('',*,*,#549,.F.);
#1234=ORIENTED_EDGE('',*,*,#1202,.F.);
#1235=ORIENTED_EDGE('',*,*,#516,.F.);
#1236=EDGE_LOOP('',(#1232,#1233,#1234,#1235));
#1237=FACE_BOUND('',#1236,.T.);
#1238=ADVANCED_FACE('F265',(#1237),#1231,.T.);
#1239=CLOSED_SHELL('',(#58,#85,#125,#277,#429,#451,#463,#480,#492,#527,#562,#593,#617,#641,#658,
#689,#713,#737,#754,#785,#809,#833,#850,#881,#905,#929,#946,#964,#995,#1019,#1043,#1060,#1078,
#1109,#1133,#1157,#1174,#1192,#1209,#1226,#1238));
#1240=MANIFOLD_SOLID_BREP('B2',#1239);
#1241=ADVANCED_BREP_SHAPE_REPRESENTATION('',(#18,#1240),#14);
#1242=SHAPE_DEFINITION_REPRESENTATION(#9,#1241);
ENDSEC;
END-ISO-10303-21;
